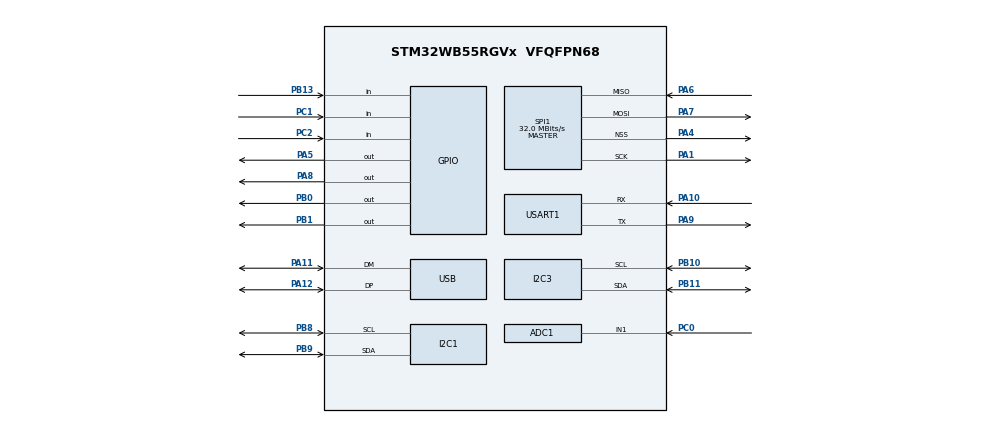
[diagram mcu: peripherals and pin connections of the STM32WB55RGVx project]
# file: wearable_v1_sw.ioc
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ADC1.Channel-0\#ChannelRegularConversion=ADC_CHANNEL_1
ADC1.NbrOfConversionFlag=1
ADC1.OffsetNumber-0\#ChannelRegularConversion=ADC_OFFSET_NONE
ADC1.Rank-0\#ChannelRegularConversion=1
ADC1.SamplingTime-0\#ChannelRegularConversion=ADC_SAMPLETIME_2CYCLES_5
ADC1.master=1
FREERTOS.Tasks01=defaultTask,24,128,StartDefaultTask,Default,NULL,Dynamic,NULL,NULL
I2C1.Timing=0x10B17DB5
I2C3.Timing=0x10B17DB5
Mcu.Family=STM32WB
Mcu.Name=STM32WB55RGVx
Mcu.Package=VFQFPN68
NVIC.HSEM_IRQn=true\:5\:0\:false\:false\:true\:true\:false\:true\:true
NVIC.IPCC_C1_RX_IRQn=true\:5\:0\:false\:false\:true\:true\:true\:true\:true
NVIC.IPCC_C1_TX_IRQn=true\:5\:0\:false\:false\:true\:true\:true\:true\:true
NVIC.PriorityGroup=NVIC_PRIORITYGROUP_4
NVIC.RTC_WKUP_IRQn=true\:5\:0\:false\:false\:true\:true\:true\:true\:true
NVIC.TIM1_UP_TIM16_IRQn=true\:15\:0\:false\:false\:true\:false\:false\:true\:true
NVIC.TimeBase=TIM1_UP_TIM16_IRQn
NVIC.TimeBaseIP=TIM1
NVIC.USB_LP_IRQn=true\:5\:0\:false\:false\:true\:true\:false\:true\:true
PA1.Mode=Full_Duplex_Master
PA1.Signal=SPI1_SCK
PA10.Mode=Asynchronous
PA10.Signal=USART1_RX
PA11.Mode=Device
PA11.Signal=USB_DM
PA12.Mode=Device
PA12.Signal=USB_DP
PA13.Mode=Serial_Wire
PA13.Signal=SYS_JTMS-SWDIO
PA14.Mode=Serial_Wire
PA14.Signal=SYS_JTCK-SWCLK
PA4.Mode=NSS_Signal_Hard_Output
PA4.Signal=SPI1_NSS
PA5.Signal=GPIO_Output
PA6.Mode=Full_Duplex_Master
PA6.Signal=SPI1_MISO
PA7.Mode=Full_Duplex_Master
PA7.Signal=SPI1_MOSI
PA8.Signal=GPIO_Output
PA9.Mode=Asynchronous
PA9.Signal=USART1_TX
PB0.Signal=GPIO_Output
PB1.Signal=GPIO_Output
PB10.Mode=I2C
PB10.Signal=I2C3_SCL
PB11.Mode=I2C
PB11.Signal=I2C3_SDA
PB13.Signal=GPIO_Input
PB8.Mode=I2C
PB8.Signal=I2C1_SCL
PB9.Mode=I2C
PB9.Signal=I2C1_SDA
PC0.Signal=ADCx_IN1
PC1.Signal=GPIO_Input
PC14-OSC32_IN.Mode=LSE-External-Oscillator
PC14-OSC32_IN.Signal=RCC_OSC32_IN
PC15-OSC32_OUT.Mode=LSE-External-Oscillator
PC15-OSC32_OUT.Signal=RCC_OSC32_OUT
PC2.Signal=GPIO_Input
ProjectManager.HeapSize=0x400
ProjectManager.StackSize=0x1000
ProjectManager.TargetToolchain=Makefile
RCC.ADCFreq_Value=48000000
RCC.AHB2CLKDivider=RCC_SYSCLK_DIV2
RCC.AHBFreq_Value=64000000
RCC.APB1Freq_Value=64000000
RCC.APB1TimFreq_Value=64000000
RCC.APB2Freq_Value=64000000
RCC.APB2TimFreq_Value=64000000
RCC.APB3Freq_Value=16000000
RCC.Cortex2_Div=SYSTICK_CLKSOURCE_HCLK_DIV8
RCC.CortexFreq_Value=64000000
RCC.HCLKFreq_Value=64000000
RCC.HSE_VALUE=32000000
RCC.HSI48_VALUE=48000000
RCC.HSI_VALUE=16000000
RCC.PLLN=32
RCC.PLLSAI1N=24
RCC.RFWKPClockSelection=RCC_RFWKPCLKSOURCE_LSE
RCC.RTCClockSelection=RCC_RTCCLKSOURCE_LSE
RCC.SYSCLKFreq_VALUE=64000000
RCC.SYSCLKSource=RCC_SYSCLKSOURCE_PLLCLK
RCC.USBFreq_Value=48000000
RCC.VCOOutputFreq_Value=128000000
SH.ADCx_IN1.0=ADC1_IN1,IN1-Single-Ended
SPI1.CalculateBaudRate=32.0 MBits/s
SPI1.Direction=SPI_DIRECTION_2LINES
SPI1.Mode=SPI_MODE_MASTER
SPI1.VirtualNSS=VM_NSSHARD
SPI1.VirtualType=VM_MASTER
USART1.VirtualMode-Asynchronous=VM_ASYNC
USB_DEVICE.CLASS_NAME_FS=CDC
USB_DEVICE.VirtualMode=Cdc
USB_DEVICE.VirtualModeFS=Cdc_FS
VP_FREERTOS_VS_CMSIS_V2.Mode=CMSIS_V2
VP_HSEM_VS_HSEM.Mode=HSEM_Activate
VP_IPCC_VS_IPCC.Mode=IPCC_Activate
VP_MEMORYMAP_VS_MEMORYMAP.Mode=CurAppReg
VP_RTC_VS_RTC_Activate.Mode=RTC_Enabled
VP_RTC_VS_RTC_WakeUp_intern.Mode=WakeUp
VP_SYS_VS_tim1.Mode=TIM1
VP_USB_DEVICE_VS_USB_DEVICE_CDC_FS.Mode=CDC_FS
board=custom

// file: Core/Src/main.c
/* USER CODE BEGIN Header */
/**
  ******************************************************************************
  * @file           : main.c
  * @brief          : Main program body
  ******************************************************************************
  * @attention
  *
  * Copyright (c) 2024 STMicroelectronics.
  * All rights reserved.
  *
  * This software is licensed under terms that can be found in the LICENSE file
  * in the root directory of this software component.
  * If no LICENSE file comes with this software, it is provided AS-IS.
  *
  ******************************************************************************
  */
/* USER CODE END Header */
#include "main.h"
#include "cmsis_os.h"
#include "adc.h"
#include "i2c.h"
#include "ipcc.h"
#include "memorymap.h"
#include "rf.h"
#include "rtc.h"
#include "spi.h"
#include "usart.h"
#include "usb_device.h"
#include "gpio.h"

void SystemClock_Config(void);
void PeriphCommonClock_Config(void);
void MX_FREERTOS_Init(void);

int main(void)
{

  /* MCU Configuration--------------------------------------------------------*/

  /* Reset of all peripherals, Initializes the Flash interface and the Systick. */
  HAL_Init();
  /* Config code for STM32_WPAN (HSE Tuning must be done before system clock configuration) */
  MX_APPE_Config();

  /* Configure the system clock */
  SystemClock_Config();

  /* Configure the peripherals common clocks */
  PeriphCommonClock_Config();

  /* IPCC initialisation */
  MX_IPCC_Init();

  /* Initialize all configured peripherals */
  MX_GPIO_Init();
  MX_SPI1_Init();
  MX_ADC1_Init();
  MX_I2C1_Init();
  MX_I2C3_Init();
  MX_RTC_Init();
  MX_USART1_UART_Init();
  MX_RF_Init();

  /* Init scheduler */
  osKernelInitialize();
  /* Init code for STM32_WPAN */
  MX_APPE_Init();

  /* Call init function for freertos objects (in cmsis_os2.c) */
  MX_FREERTOS_Init();

  /* Start scheduler */
  osKernelStart();

  /* We should never get here as control is now taken by the scheduler */

  /* Infinite loop */
  while (1)
  {

  }
}

void SystemClock_Config(void)
{
  RCC_OscInitTypeDef RCC_OscInitStruct = {0};
  RCC_ClkInitTypeDef RCC_ClkInitStruct = {0};

  /** Macro to configure the PLL multiplication factor
  */
  __HAL_RCC_PLL_PLLM_CONFIG(RCC_PLLM_DIV1);

  /** Macro to configure the PLL clock source
  */
  __HAL_RCC_PLL_PLLSOURCE_CONFIG(RCC_PLLSOURCE_MSI);

  /** Configure LSE Drive Capability
  */
  HAL_PWR_EnableBkUpAccess();
  __HAL_RCC_LSEDRIVE_CONFIG(RCC_LSEDRIVE_MEDIUMHIGH);

  /** Configure the main internal regulator output voltage
  */
  __HAL_PWR_VOLTAGESCALING_CONFIG(PWR_REGULATOR_VOLTAGE_SCALE1);

  /** Initializes the RCC Oscillators according to the specified parameters
  * in the RCC_OscInitTypeDef structure.
  */
  RCC_OscInitStruct.OscillatorType = RCC_OSCILLATORTYPE_HSI|RCC_OSCILLATORTYPE_HSE
                              |RCC_OSCILLATORTYPE_LSE|RCC_OSCILLATORTYPE_MSI;
  RCC_OscInitStruct.HSEState = RCC_HSE_ON;
  RCC_OscInitStruct.LSEState = RCC_LSE_ON;
  RCC_OscInitStruct.HSIState = RCC_HSI_ON;
  RCC_OscInitStruct.MSIState = RCC_MSI_ON;
  RCC_OscInitStruct.HSICalibrationValue = RCC_HSICALIBRATION_DEFAULT;
  RCC_OscInitStruct.MSICalibrationValue = RCC_MSICALIBRATION_DEFAULT;
  RCC_OscInitStruct.MSIClockRange = RCC_MSIRANGE_6;
  RCC_OscInitStruct.PLL.PLLState = RCC_PLL_NONE;
  if (HAL_RCC_OscConfig(&RCC_OscInitStruct) != HAL_OK)
  {
    Error_Handler();
  }

  /** Configure the SYSCLKSource, HCLK, PCLK1 and PCLK2 clocks dividers
  */
  RCC_ClkInitStruct.ClockType = RCC_CLOCKTYPE_HCLK4|RCC_CLOCKTYPE_HCLK2
                              |RCC_CLOCKTYPE_HCLK|RCC_CLOCKTYPE_SYSCLK
                              |RCC_CLOCKTYPE_PCLK1|RCC_CLOCKTYPE_PCLK2;
  RCC_ClkInitStruct.SYSCLKSource = RCC_SYSCLKSOURCE_HSE;
  RCC_ClkInitStruct.AHBCLKDivider = RCC_SYSCLK_DIV1;
  RCC_ClkInitStruct.APB1CLKDivider = RCC_HCLK_DIV1;
  RCC_ClkInitStruct.APB2CLKDivider = RCC_HCLK_DIV1;
  RCC_ClkInitStruct.AHBCLK2Divider = RCC_SYSCLK_DIV1;
  RCC_ClkInitStruct.AHBCLK4Divider = RCC_SYSCLK_DIV1;

  if (HAL_RCC_ClockConfig(&RCC_ClkInitStruct, FLASH_LATENCY_1) != HAL_OK)
  {
    Error_Handler();
  }

  /** Enable MSI Auto calibration
  */
  HAL_RCCEx_EnableMSIPLLMode();
}

void PeriphCommonClock_Config(void)
{
  RCC_PeriphCLKInitTypeDef PeriphClkInitStruct = {0};

  /** Initializes the peripherals clock
  */
  PeriphClkInitStruct.PeriphClockSelection = RCC_PERIPHCLK_SMPS|RCC_PERIPHCLK_RFWAKEUP
                              |RCC_PERIPHCLK_USB|RCC_PERIPHCLK_ADC;
  PeriphClkInitStruct.PLLSAI1.PLLN = 24;
  PeriphClkInitStruct.PLLSAI1.PLLP = RCC_PLLP_DIV2;
  PeriphClkInitStruct.PLLSAI1.PLLQ = RCC_PLLQ_DIV2;
  PeriphClkInitStruct.PLLSAI1.PLLR = RCC_PLLR_DIV2;
  PeriphClkInitStruct.PLLSAI1.PLLSAI1ClockOut = RCC_PLLSAI1_USBCLK|RCC_PLLSAI1_ADCCLK;
  PeriphClkInitStruct.UsbClockSelection = RCC_USBCLKSOURCE_PLLSAI1;
  PeriphClkInitStruct.AdcClockSelection = RCC_ADCCLKSOURCE_PLLSAI1;
  PeriphClkInitStruct.RFWakeUpClockSelection = RCC_RFWKPCLKSOURCE_LSE;
  PeriphClkInitStruct.SmpsClockSelection = RCC_SMPSCLKSOURCE_HSE;
  PeriphClkInitStruct.SmpsDivSelection = RCC_SMPSCLKDIV_RANGE1;

  if (HAL_RCCEx_PeriphCLKConfig(&PeriphClkInitStruct) != HAL_OK)
  {
    Error_Handler();
  }
}

void HAL_TIM_PeriodElapsedCallback(TIM_HandleTypeDef *htim)
{
  if (htim->Instance == TIM1) {
    HAL_IncTick();
  }
}

void Error_Handler(void)
{
  __disable_irq();
  while (1)
  {
  }
}
